VERSION 5.7 ;
BUSBITCHARS "[]" ;
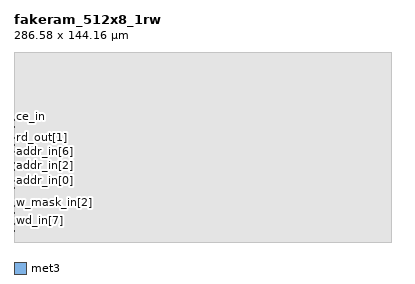
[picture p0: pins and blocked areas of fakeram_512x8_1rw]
MACRO fakeram_512x8_1rw
  FOREIGN fakeram_512x8_1rw 0 0 ;
  SYMMETRY X Y R90 ;
  SIZE 286.580 BY 144.160 ;
  CLASS BLOCK ;
  PIN wd_in[0]
    DIRECTION INPUT ;
    USE SIGNAL ;
    SHAPE ABUTMENT ;
    PORT
      LAYER met3 ;
      RECT 0.000 2.720 0.300 3.020 ;
    END
  END wd_in[0]
  PIN wd_in[1]
    DIRECTION INPUT ;
    USE SIGNAL ;
    SHAPE ABUTMENT ;
    PORT
      LAYER met3 ;
      RECT 0.000 5.440 0.300 5.740 ;
    END
  END wd_in[1]
  PIN wd_in[2]
    DIRECTION INPUT ;
    USE SIGNAL ;
    SHAPE ABUTMENT ;
    PORT
      LAYER met3 ;
      RECT 0.000 8.160 0.300 8.460 ;
    END
  END wd_in[2]
  PIN wd_in[3]
    DIRECTION INPUT ;
    USE SIGNAL ;
    SHAPE ABUTMENT ;
    PORT
      LAYER met3 ;
      RECT 0.000 10.880 0.300 11.180 ;
    END
  END wd_in[3]
  PIN wd_in[4]
    DIRECTION INPUT ;
    USE SIGNAL ;
    SHAPE ABUTMENT ;
    PORT
      LAYER met3 ;
      RECT 0.000 13.600 0.300 13.900 ;
    END
  END wd_in[4]
  PIN wd_in[5]
    DIRECTION INPUT ;
    USE SIGNAL ;
    SHAPE ABUTMENT ;
    PORT
      LAYER met3 ;
      RECT 0.000 16.320 0.300 16.620 ;
    END
  END wd_in[5]
  PIN wd_in[6]
    DIRECTION INPUT ;
    USE SIGNAL ;
    SHAPE ABUTMENT ;
    PORT
      LAYER met3 ;
      RECT 0.000 19.040 0.300 19.340 ;
    END
  END wd_in[6]
  PIN wd_in[7]
    DIRECTION INPUT ;
    USE SIGNAL ;
    SHAPE ABUTMENT ;
    PORT
      LAYER met3 ;
      RECT 0.000 21.760 0.300 22.060 ;
    END
  END wd_in[7]
  PIN w_mask_in[0]
    DIRECTION INPUT ;
    USE SIGNAL ;
    SHAPE ABUTMENT ;
    PORT
      LAYER met3 ;
      RECT 0.000 24.480 0.300 24.780 ;
    END
  END w_mask_in[0]
  PIN w_mask_in[1]
    DIRECTION INPUT ;
    USE SIGNAL ;
    SHAPE ABUTMENT ;
    PORT
      LAYER met3 ;
      RECT 0.000 27.200 0.300 27.500 ;
    END
  END w_mask_in[1]
  PIN w_mask_in[2]
    DIRECTION INPUT ;
    USE SIGNAL ;
    SHAPE ABUTMENT ;
    PORT
      LAYER met3 ;
      RECT 0.000 29.920 0.300 30.220 ;
    END
  END w_mask_in[2]
  PIN w_mask_in[3]
    DIRECTION INPUT ;
    USE SIGNAL ;
    SHAPE ABUTMENT ;
    PORT
      LAYER met3 ;
      RECT 0.000 32.640 0.300 32.940 ;
    END
  END w_mask_in[3]
  PIN w_mask_in[4]
    DIRECTION INPUT ;
    USE SIGNAL ;
    SHAPE ABUTMENT ;
    PORT
      LAYER met3 ;
      RECT 0.000 35.360 0.300 35.660 ;
    END
  END w_mask_in[4]
  PIN w_mask_in[5]
    DIRECTION INPUT ;
    USE SIGNAL ;
    SHAPE ABUTMENT ;
    PORT
      LAYER met3 ;
      RECT 0.000 38.080 0.300 38.380 ;
    END
  END w_mask_in[5]
  PIN w_mask_in[6]
    DIRECTION INPUT ;
    USE SIGNAL ;
    SHAPE ABUTMENT ;
    PORT
      LAYER met3 ;
      RECT 0.000 40.800 0.300 41.100 ;
    END
  END w_mask_in[6]
  PIN w_mask_in[7]
    DIRECTION INPUT ;
    USE SIGNAL ;
    SHAPE ABUTMENT ;
    PORT
      LAYER met3 ;
      RECT 0.000 43.520 0.300 43.820 ;
    END
  END w_mask_in[7]
  PIN addr_in[0]
    DIRECTION INPUT ;
    USE SIGNAL ;
    SHAPE ABUTMENT ;
    PORT
      LAYER met3 ;
      RECT 0.000 46.240 0.300 46.540 ;
    END
  END addr_in[0]
  PIN addr_in[1]
    DIRECTION INPUT ;
    USE SIGNAL ;
    SHAPE ABUTMENT ;
    PORT
      LAYER met3 ;
      RECT 0.000 48.960 0.300 49.260 ;
    END
  END addr_in[1]
  PIN addr_in[2]
    DIRECTION INPUT ;
    USE SIGNAL ;
    SHAPE ABUTMENT ;
    PORT
      LAYER met3 ;
      RECT 0.000 51.680 0.300 51.980 ;
    END
  END addr_in[2]
  PIN addr_in[3]
    DIRECTION INPUT ;
    USE SIGNAL ;
    SHAPE ABUTMENT ;
    PORT
      LAYER met3 ;
      RECT 0.000 54.400 0.300 54.700 ;
    END
  END addr_in[3]
  PIN addr_in[4]
    DIRECTION INPUT ;
    USE SIGNAL ;
    SHAPE ABUTMENT ;
    PORT
      LAYER met3 ;
      RECT 0.000 57.120 0.300 57.420 ;
    END
  END addr_in[4]
  PIN addr_in[5]
    DIRECTION INPUT ;
    USE SIGNAL ;
    SHAPE ABUTMENT ;
    PORT
      LAYER met3 ;
      RECT 0.000 59.840 0.300 60.140 ;
    END
  END addr_in[5]
  PIN addr_in[6]
    DIRECTION INPUT ;
    USE SIGNAL ;
    SHAPE ABUTMENT ;
    PORT
      LAYER met3 ;
      RECT 0.000 62.560 0.300 62.860 ;
    END
  END addr_in[6]
  PIN addr_in[7]
    DIRECTION INPUT ;
    USE SIGNAL ;
    SHAPE ABUTMENT ;
    PORT
      LAYER met3 ;
      RECT 0.000 65.280 0.300 65.580 ;
    END
  END addr_in[7]
  PIN addr_in[8]
    DIRECTION INPUT ;
    USE SIGNAL ;
    SHAPE ABUTMENT ;
    PORT
      LAYER met3 ;
      RECT 0.000 68.000 0.300 68.300 ;
    END
  END addr_in[8]
  PIN rd_out[0]
    DIRECTION OUTPUT ;
    USE SIGNAL ;
    SHAPE ABUTMENT ;
    PORT
      LAYER met3 ;
      RECT 0.000 70.720 0.300 71.020 ;
    END
  END rd_out[0]
  PIN rd_out[1]
    DIRECTION OUTPUT ;
    USE SIGNAL ;
    SHAPE ABUTMENT ;
    PORT
      LAYER met3 ;
      RECT 0.000 73.440 0.300 73.740 ;
    END
  END rd_out[1]
  PIN rd_out[2]
    DIRECTION OUTPUT ;
    USE SIGNAL ;
    SHAPE ABUTMENT ;
    PORT
      LAYER met3 ;
      RECT 0.000 76.160 0.300 76.460 ;
    END
  END rd_out[2]
  PIN rd_out[3]
    DIRECTION OUTPUT ;
    USE SIGNAL ;
    SHAPE ABUTMENT ;
    PORT
      LAYER met3 ;
      RECT 0.000 78.880 0.300 79.180 ;
    END
  END rd_out[3]
  PIN rd_out[4]
    DIRECTION OUTPUT ;
    USE SIGNAL ;
    SHAPE ABUTMENT ;
    PORT
      LAYER met3 ;
      RECT 0.000 81.600 0.300 81.900 ;
    END
  END rd_out[4]
  PIN rd_out[5]
    DIRECTION OUTPUT ;
    USE SIGNAL ;
    SHAPE ABUTMENT ;
    PORT
      LAYER met3 ;
      RECT 0.000 84.320 0.300 84.620 ;
    END
  END rd_out[5]
  PIN rd_out[6]
    DIRECTION OUTPUT ;
    USE SIGNAL ;
    SHAPE ABUTMENT ;
    PORT
      LAYER met3 ;
      RECT 0.000 87.040 0.300 87.340 ;
    END
  END rd_out[6]
  PIN rd_out[7]
    DIRECTION OUTPUT ;
    USE SIGNAL ;
    SHAPE ABUTMENT ;
    PORT
      LAYER met3 ;
      RECT 0.000 89.760 0.300 90.060 ;
    END
  END rd_out[7]
  PIN clk
    DIRECTION INPUT ;
    USE SIGNAL ;
    SHAPE ABUTMENT ;
    PORT
      LAYER met3 ;
      RECT 0.000 92.480 0.300 92.780 ;
    END
  END clk
  PIN ce_in
    DIRECTION INPUT ;
    USE SIGNAL ;
    SHAPE ABUTMENT ;
    PORT
      LAYER met3 ;
      RECT 0.000 95.200 0.300 95.500 ;
    END
  END ce_in
  PIN we_in
    DIRECTION INPUT ;
    USE SIGNAL ;
    SHAPE ABUTMENT ;
    PORT
      LAYER met3 ;
      RECT 0.000 97.920 0.300 98.220 ;
    END
  END we_in
  OBS
    LAYER met1 ;
      RECT 0.000 0.000 286.580 144.160 ;
    LAYER met2 ;
      RECT 0.000 0.000 286.580 144.160 ;
    LAYER met3 ;
      RECT 0.000 0.000 286.580 144.160 ;
  END
END fakeram_512x8_1rw
END LIBRARY
